VERSION 5.8 ;
BUSBITCHARS "<>" ;
DIVIDERCHAR "/" ;

UNITS
   DATABASE MICRONS 1000 ;
END UNITS

LAYER M1
   TYPE ROUTING ;
   MASK 2 ;
   DIRECTION DIAG45 ;
   WIDTH 0.2 ;
   PITCH 0.4 0.5 ;
   OFFSET 0.05 0.06 ;
   DIAGPITCH 0.3 ;
   DIAGSPACING 0.15 ;
   DIAGWIDTH 0.1 ;
   DIAGMINEDGELENGTH 0.08 ;
   MAXWIDTH 2 ;
   MINWIDTH 0.1 ;
   MINSIZE 0.1 0.2 0.3 0.4 ;
   MINENCLOSEDAREA 0.4 WIDTH 0.15 ;
   MINENCLOSEDAREA 0.8 ;
   PROTRUSIONWIDTH 0.3 LENGTH 0.6 WIDTH 1.2 ;
   SPACINGTABLE
      TWOWIDTHS
         WIDTH 0.1          0.2 0.3
         WIDTH 0.2 PRL 0.15 0.3 0.4 ;
   SPLITWIREWIDTH 0.5 ;
   MINIMUMDENSITY 4 ;
   MAXIMUMDENSITY 10 ;
   DENSITYCHECKSTEP 0.2 ;
   DENSITYCHECKWINDOW 1 1 ;
   FILLACTIVESPACING 0.4 ;
   ACCURRENTDENSITY PEAK
      FREQUENCY 1000000 100000000 ;
      WIDTH 0.1 0.2 ;
      TABLEENTRIES 0.0000005 0.0000004 ;
   ACCURRENTDENSITY AVERAGE 5.5 ;
   DCCURRENTDENSITY AVERAGE 4.9 ;
   ANTENNAMODEL OXIDE1 ;
      ANTENNAAREARATIO 100 ;
      ANTENNADIFFAREARATIO PWL ( ( 0.1 1.0 ) ( 0.2 1.5 ) ) ;
      ANTENNASIDEAREARATIO 50 ;
END M1

LAYER V1
   TYPE CUT ;
   WIDTH 0.15 ;
   ARRAYSPACING LONGARRAY WIDTH 0.5 CUTSPACING 0.2
      ARRAYCUTS 3 SPACING 1.0
      ARRAYCUTS 4 SPACING 1.5 ;
   PREFERENCLOSURE BELOW 0.06 0.01 ;
   ENCLOSURE ABOVE 0.05 0.01 ;
   ENCLOSURE 0.02 0.02 WIDTH 1.0 ;
   RESISTANCE 10.0 ;
   DCCURRENTDENSITY AVERAGE
      CUTAREA 2.0 5.0 ;
      TABLEENTRIES 0.0000005 0.0000004 ;
   ANTENNAMODEL OXIDE1 ;
      ANTENNAAREARATIO 80 ;
END V1

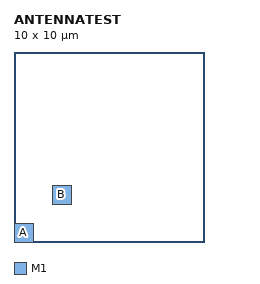
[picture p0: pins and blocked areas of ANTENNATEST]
MACRO ANTENNATEST
   CLASS CORE ;
   ORIGIN 0 0 ;
   SIZE 10 BY 10 ;
   SITE CORE 0 0 N DO 2 BY 1 STEP 10 0 ;
   SITE CORE 5 5 FN ;

   PIN A
      DIRECTION INPUT ;
      TAPERRULE RULE1 ;
      SUPPLYSENSITIVITY vddpin1 ;
      GROUNDSENSITIVITY gndpin ;
      RISESLEWLIMIT 0.01 ;
      FALLSLEWLIMIT 0.02 ;
      MAXLOAD 0.1 ;
      ANTENNAPARTIALMETALAREA 1.5 LAYER M1 ;
      ANTENNAMODEL OXIDE1 ;
         ANTENNAGATEAREA 2.0 LAYER M1 ;
      PORT
         CLASS CORE ;
         LAYER M1 SPACING 0.05 ;
            RECT 0 0 1 1 ;
            VIA 0.2 0.2 MYVIA ;
      END
   END A

   PIN B
      DIRECTION FEEDTHRU ;
      PORT
         LAYER M1 ;
            RECT 2 2 3 3 ;
      END
   END B

   OBS
      LAYER V1 EXCEPTPGNET ;
         RECT 0 0 1 1 ;
   END
END ANTENNATEST
